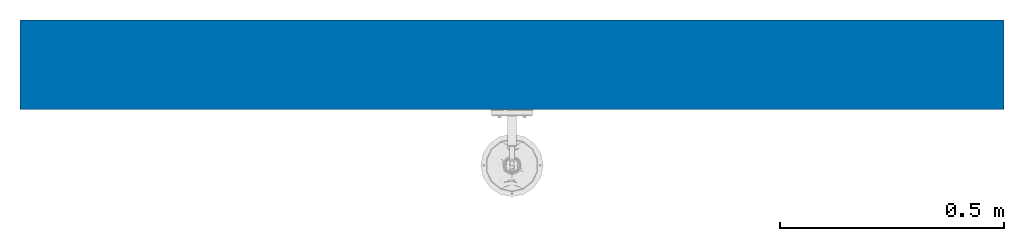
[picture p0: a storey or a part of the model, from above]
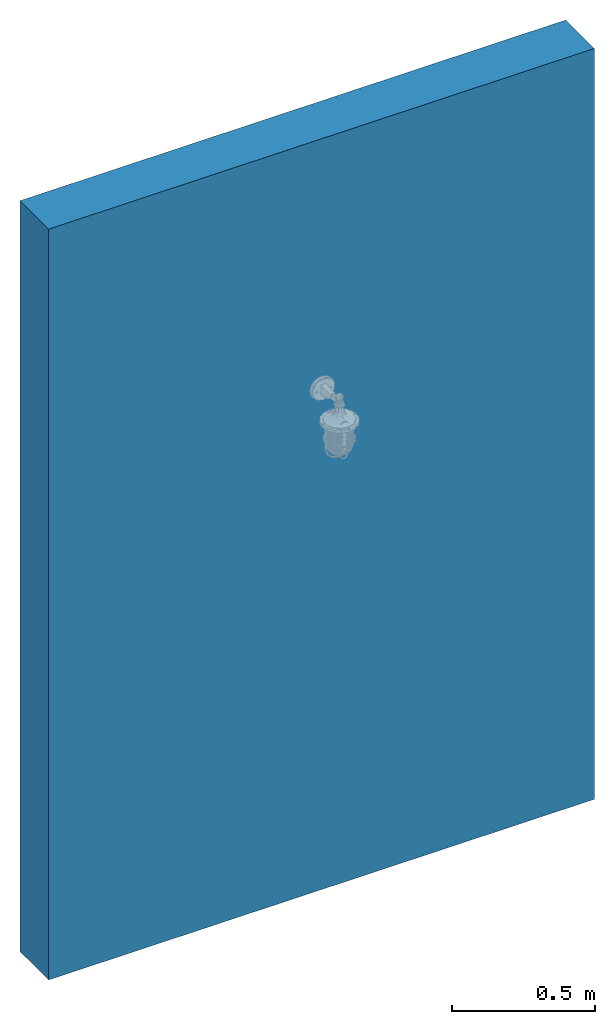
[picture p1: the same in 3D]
Properties of the parts of a building model (IFC2X3)

# File
Description: ViewDefinition [CoordinationView_V2.0], RevitIdentifiers [ContentGUID: ddec75ef-0b32-4126-948c-f439e7b69921, VersionGUID: c3746ebe-c188-4453-8e02-65d9f5aefd86, NumberOfSaves: 0], CoordinateReference [CoordinateBase: Shared Coordinates]
File name: Project1.ifc
Time: 2026-02-06T14:46:38+03:30
Written by: ODA SDAI 24.12
Made in: Autodesk Revit 25.4.0.32 (ENU) - IFC 25.4.0.32

# IfcProject, Project Number
LongName: home desing; Phase: Project Status

# IfcSite, Default
RefLatitude: 42, 21, 30, 344238; RefLongitude: -71, -3, -35, -194702; RefElevation: 0 m

# IfcBuilding
Pset_BuildingCommon - NumberOfStoreys: 1

# IfcBuildingStorey: Level:8mm Head (5)
Pset_AirSideSystemInformation - sets with these values: 2
Name | LongName = Name | Elevation (m)
Level 1 | Level 1 | 0
Level 2 | Level 2 | 3.2
Level 3 | Level 3 | 6.4
Level 4 | Level 4 | 9.6
Level 5 | Level 5 | 12.8

# IfcDistributionPort, Port_205531_1
Description: Flow; FlowDirection: SOURCEANDSINK

# IfcFlowTerminal: Tiller Wall Lantern:Variant2-Antique Brass, Tiller Wall Lantern:Variant2-Antique Brass:205531
In: Level 1
Type - Material: Antique Brass, Mat-Glass, Mat-Lamp holder, Mat-Lamp
Type - Pset_ManufacturerTypeInformation - Manufacturer: Lampfix
Pset_DistributionFlowElementCommon - Reference: Variant2-Antique Brass; sets with these values: 2

# IfcWallStandardCase: Basic Wall:Wall 20cm2, Basic Wall:Wall 20cm2:202169
In: Level 1
Type - PredefinedType: STANDARD; Material: Default Wall 0.2 m
Pset_QuantityTakeOff - Reference: Wall 20cm2; sets with these values: 2
Pset_WallCommon - Reference: Wall 20cm2; IsExternal: yes; ExtendToStructure: no; LoadBearing: no
